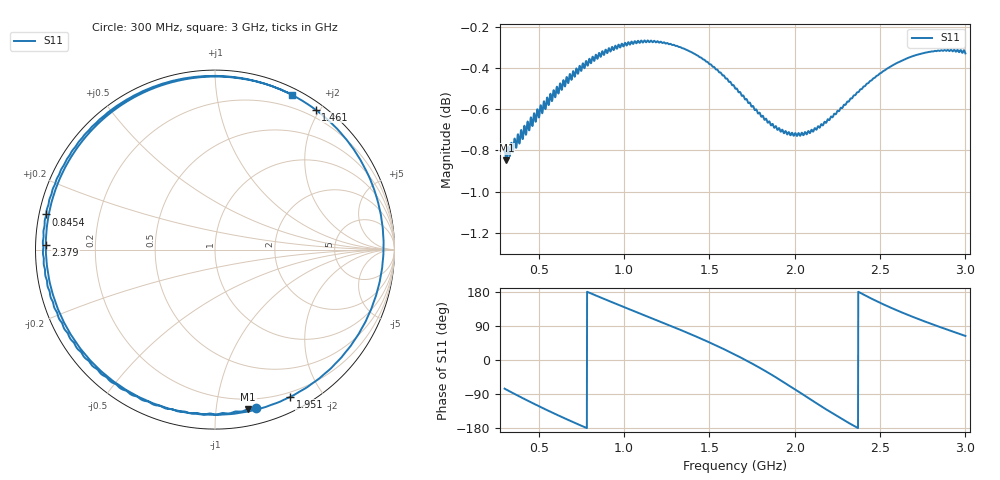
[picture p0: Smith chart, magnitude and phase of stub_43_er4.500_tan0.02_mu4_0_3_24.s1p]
! Chirptenna · simulación 3D de un stub abierto
# HZ S RI R 50
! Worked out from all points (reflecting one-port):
!   2001 points, 300 MHz to 3 GHz, reference 50 ohm
!   lowest |S11| = -0.8 dB at 310.8 MHz (marker M1), VSWR 20.51, Z = 6.1 - j61.1 ohm
!   phase of S11 starts at -76 deg and turns -581 deg over the sweep
!   S11 on the Smith chart (normalised r, x): 300 MHz: 0.12, -1.28; 845.4 MHz: 0.02, +0.10; 1.461 GHz: 0.10, +1.95; 1.951 GHz: 0.15, -1.62; 2.379 GHz: 0.03, +0.01; 3 GHz: 0.07, +1.61
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3e8  0.227 -0.8827
3.108e8  0.185 -0.8879
3.864e8  -0.0974 -0.9104
4.62e8  -0.3668 -0.8488
5.6055e8  -0.6588 -0.6651
6.375e8  -0.8246 -0.4605
7.4685e8  -0.9465 -0.1177
8.454e8  -0.94 0.1957
9.75e8  -0.7829 0.5664
1.1505e9  -0.3692 0.896
1.3125e9  0.1215 0.9592
1.461e9  0.5601 0.7794
1.5609e9  0.7916 0.5302
1.65e9  0.9154 0.2323
1.72695e9  0.9346 -0.0618
1.8012e9  0.8603 -0.3529
1.87545e9  0.6877 -0.618
1.95105e9  0.4186 -0.8205
1.9875e9  0.2632 -0.8823
2.06445e9  -0.0925 -0.9164
2.1387e9  -0.4246 -0.8211
2.2359e9  -0.7602 -0.5373
2.325e9  -0.9191 -0.1911
2.379e9  -0.9426 0.0266
2.5032e9  -0.8271 0.4721
2.6625e9  -0.4669 0.8393
2.8245e9  -0.0217 0.964
3e9  0.43 0.8616
